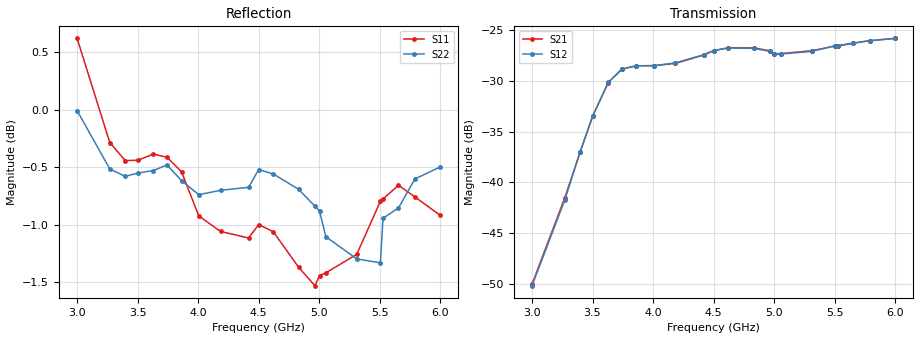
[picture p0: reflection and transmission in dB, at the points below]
!  26/11/2025  16:34:56
! Ref Plane: 0.000 mm
# MHZ S MA R  50
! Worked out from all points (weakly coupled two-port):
!   401 points, 3 GHz to 6 GHz, reference 50 ohm
!   highest |S21| = -25.82 dB at 6 GHz (marker M1); lowest = -50.0 dB at 3 GHz (marker M2)
!   lowest |S11| = -1.5 dB at 4.965 GHz (marker M3), VSWR 11.38, Z = 9.67 - j54.3 ohm
!   |S11| at or under -10 dB: nowhere
!   |S22| runs from -1.3 to 0.1 dB; largest |S21 - S12| = 0.0021
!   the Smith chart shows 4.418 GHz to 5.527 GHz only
!   S11 on the Smith chart (normalised r, x): 4.418 GHz: 0.13, +0.98; 4.62 GHz: 1.21, +4.18; 4.83 GHz: 0.59, -2.49; 5.055 GHz: 0.12, -0.69; 5.31 GHz: 0.07, +0.01; 5.527 GHz: 0.06, +0.61
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3000  1.074 -137.6  0.003161 48.2  0.003106 50.6  0.999 -106.1
3270  0.9676 152.2  0.008386 -18.5  0.00818 -15.2  0.9424 -171.0
3397.5  0.9503 109.0  0.01412 -58.1  0.01414 -57.2  0.9354 150.3
3502.5  0.9506 66.3  0.02135 -98.4  0.02126 -97.1  0.9385 112.4
3630  0.9565 11.3  0.03096 -154.4  0.03108 -153.0  0.9409 57.2
3742.5  0.9534 -38.4  0.03609 155.7  0.03615 157.1  0.9461 8.9
3862.5  0.9398 -86.3  0.03749 106.5  0.03753 108.0  0.9314 -39.8
4005  0.8991 -138.0  0.03759 55.6  0.03745 56.8  0.9184 -89.5
4185  0.8852 164.5  0.03851 -1.9  0.03876 0.3  0.9224 -146.0
4417.5  0.8794 90.5  0.04233 -73.0  0.0425 -71.4  0.9252 142.9
4500  0.8913 64.5  0.04443 -99.4  0.04458 -97.9  0.9418 117.6
4620  0.885 25.0  0.04604 -138.2  0.04584 -137.0  0.9377 79.8
4830  0.854 -41.9  0.04592 155.5  0.04568 157.0  0.9233 16.7
4965  0.8384 -84.3  0.04444 115.8  0.04414 117.3  0.9078 -22.1
5002.5  0.8468 -95.8  0.04299 105.5  0.04262 106.7  0.9035 -33.9
5055  0.8493 -110.5  0.04307 90.7  0.04282 91.6  0.8805 -49.8
5310  0.8651 179.4  0.04445 22.0  0.04414 23.4  0.8612 -123.5
5505  0.9123 121.7  0.0469 -32.1  0.04707 -30.0  0.8578 -175.7
5527.5  0.9145 117.3  0.04715 -37.4  0.04686 -35.3  0.897 178.6
5655  0.9271 80.5  0.04851 -74.0  0.04836 -71.6  0.9063 142.6
5790  0.9164 41.5  0.04976 -113.2  0.04992 -111.2  0.9329 104.7
6000  0.8996 -20.1  0.05115 -173.7  0.0511 -172.1  0.9443 50.6
